VERSION 5.7 ;
  NOWIREEXTENSIONATPIN ON ;
  DIVIDERCHAR "/" ;
  BUSBITCHARS "[]" ;
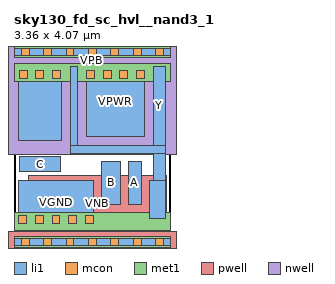
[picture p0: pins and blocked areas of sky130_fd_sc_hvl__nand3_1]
MACRO sky130_fd_sc_hvl__nand3_1
  CLASS BLOCK ;
  FOREIGN sky130_fd_sc_hvl__nand3_1 ;
  ORIGIN 0.000 0.000 ;
  SIZE 3.360 BY 4.070 ;
  PIN A
    ANTENNAGATEAREA 1.125000 ;
    PORT
      LAYER li1 ;
        RECT 2.455 0.810 2.725 1.725 ;
    END
  END A
  PIN B
    ANTENNAGATEAREA 1.125000 ;
    PORT
      LAYER li1 ;
        RECT 1.885 0.810 2.275 1.725 ;
    END
  END B
  PIN C
    ANTENNAGATEAREA 1.125000 ;
    PORT
      LAYER li1 ;
        RECT 0.125 1.505 0.995 1.835 ;
    END
  END C
  PIN VGND
    USE GROUND ;
    PORT
      LAYER li1 ;
        RECT 0.090 0.365 1.705 1.325 ;
      LAYER mcon ;
        RECT 0.095 0.395 0.265 0.565 ;
        RECT 0.455 0.395 0.625 0.565 ;
        RECT 0.815 0.395 0.985 0.565 ;
        RECT 1.175 0.395 1.345 0.565 ;
        RECT 1.535 0.395 1.705 0.565 ;
      LAYER met1 ;
        RECT 0.000 0.255 3.360 0.625 ;
    END
  END VGND
  PIN VNB
    ANTENNADIFFAREA 0.571200 ;
    PORT
      LAYER pwell ;
        RECT 0.300 0.215 3.265 1.415 ;
        RECT -0.130 -0.215 3.490 0.215 ;
      LAYER li1 ;
        RECT 0.000 -0.085 3.360 0.085 ;
      LAYER mcon ;
        RECT 0.155 -0.085 0.325 0.085 ;
        RECT 0.635 -0.085 0.805 0.085 ;
        RECT 1.115 -0.085 1.285 0.085 ;
        RECT 1.595 -0.085 1.765 0.085 ;
        RECT 2.075 -0.085 2.245 0.085 ;
        RECT 2.555 -0.085 2.725 0.085 ;
        RECT 3.035 -0.085 3.205 0.085 ;
      LAYER met1 ;
        RECT 0.000 -0.115 3.360 0.115 ;
    END
  END VNB
  PIN VPB
    ANTENNADIFFAREA 0.571200 ;
    PORT
      LAYER nwell ;
        RECT -0.330 1.885 3.690 4.485 ;
      LAYER li1 ;
        RECT 0.000 3.985 3.360 4.155 ;
      LAYER mcon ;
        RECT 0.155 3.985 0.325 4.155 ;
        RECT 0.635 3.985 0.805 4.155 ;
        RECT 1.115 3.985 1.285 4.155 ;
        RECT 1.595 3.985 1.765 4.155 ;
        RECT 2.075 3.985 2.245 4.155 ;
        RECT 2.555 3.985 2.725 4.155 ;
        RECT 3.035 3.985 3.205 4.155 ;
      LAYER met1 ;
        RECT 0.000 3.955 3.360 4.185 ;
    END
  END VPB
  PIN VPWR
    USE POWER ;
    PORT
      LAYER li1 ;
        RECT 0.090 2.175 1.020 3.755 ;
        RECT 1.550 2.255 2.800 3.755 ;
      LAYER mcon ;
        RECT 0.110 3.505 0.280 3.675 ;
        RECT 0.470 3.505 0.640 3.675 ;
        RECT 0.830 3.505 1.000 3.675 ;
        RECT 1.550 3.505 1.720 3.675 ;
        RECT 1.910 3.505 2.080 3.675 ;
        RECT 2.270 3.505 2.440 3.675 ;
        RECT 2.630 3.505 2.800 3.675 ;
      LAYER met1 ;
        RECT 0.000 3.445 3.360 3.815 ;
    END
  END VPWR
  PIN Y
    ANTENNADIFFAREA 1.065000 ;
    PORT
      LAYER li1 ;
        RECT 1.200 2.075 1.370 3.755 ;
        RECT 2.980 2.075 3.235 3.755 ;
        RECT 1.200 1.905 3.235 2.075 ;
        RECT 2.980 1.325 3.235 1.905 ;
        RECT 2.905 0.495 3.235 1.325 ;
    END
  END Y
END sky130_fd_sc_hvl__nand3_1
END LIBRARY

